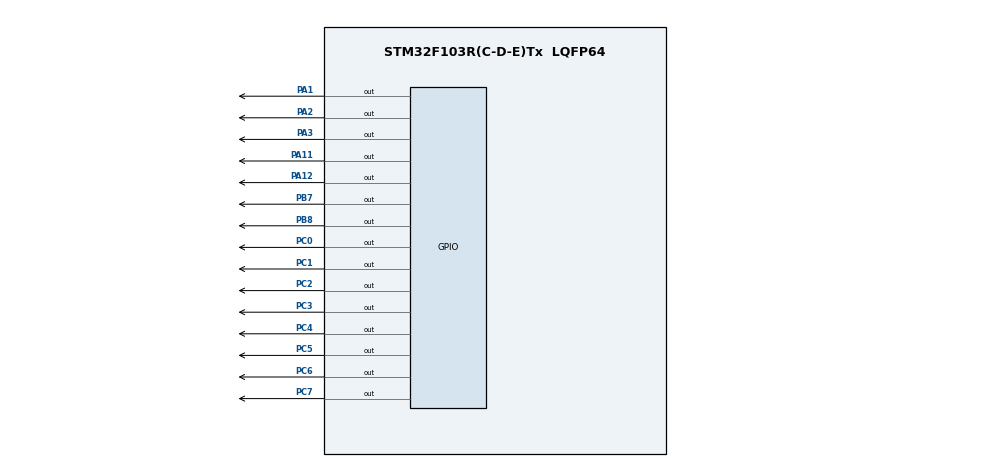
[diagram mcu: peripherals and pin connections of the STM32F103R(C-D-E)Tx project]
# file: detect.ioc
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Mcu.Family=STM32F1
Mcu.Name=STM32F103R(C-D-E)Tx
Mcu.Package=LQFP64
NVIC.PriorityGroup=NVIC_PRIORITYGROUP_4
PA1.PinState=GPIO_PIN_SET
PA1.Signal=GPIO_Output
PA11.Signal=GPIO_Output
PA12.Signal=GPIO_Output
PA2.PinState=GPIO_PIN_SET
PA2.Signal=GPIO_Output
PA3.PinState=GPIO_PIN_SET
PA3.Signal=GPIO_Output
PB7.PinState=GPIO_PIN_SET
PB7.Signal=GPIO_Output
PB8.PinState=GPIO_PIN_SET
PB8.Signal=GPIO_Output
PC0.PinState=GPIO_PIN_SET
PC0.Signal=GPIO_Output
PC1.PinState=GPIO_PIN_SET
PC1.Signal=GPIO_Output
PC2.PinState=GPIO_PIN_SET
PC2.Signal=GPIO_Output
PC3.PinState=GPIO_PIN_SET
PC3.Signal=GPIO_Output
PC4.PinState=GPIO_PIN_SET
PC4.Signal=GPIO_Output
PC5.PinState=GPIO_PIN_SET
PC5.Signal=GPIO_Output
PC6.PinState=GPIO_PIN_SET
PC6.Signal=GPIO_Output
PC7.PinState=GPIO_PIN_SET
PC7.Signal=GPIO_Output
PD0-OSC_IN.Mode=HSE-External-Oscillator
PD0-OSC_IN.Signal=RCC_OSC_IN
PD1-OSC_OUT.Mode=HSE-External-Oscillator
PD1-OSC_OUT.Signal=RCC_OSC_OUT
ProjectManager.HeapSize=0x200
ProjectManager.StackSize=0x400
ProjectManager.TargetToolchain=MDK-ARM V5
RCC.AHBFreq_Value=72000000
RCC.APB1CLKDivider=RCC_HCLK_DIV2
RCC.APB1Freq_Value=36000000
RCC.APB1TimFreq_Value=72000000
RCC.APB2CLKDivider=RCC_HCLK_DIV2
RCC.APB2Freq_Value=36000000
RCC.APB2TimFreq_Value=72000000
RCC.HCLKFreq_Value=72000000
RCC.PLLMUL=RCC_PLL_MUL9
RCC.PLLSourceVirtual=RCC_PLLSOURCE_HSE
RCC.SYSCLKFreq_VALUE=72000000
RCC.SYSCLKSource=RCC_SYSCLKSOURCE_PLLCLK
RCC.USBFreq_Value=72000000
VP_SYS_VS_ND.Mode=No_Debug
board=custom

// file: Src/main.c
/* USER CODE BEGIN Header */
/**
  ******************************************************************************
  * @file           : main.c
  * @brief          : Main program body
  ******************************************************************************
  * @attention
  *
  * <h2><center>&copy; Copyright (c) 2020 STMicroelectronics.
  * All rights reserved.</center></h2>
  *
  * This software component is licensed by ST under BSD 3-Clause license,
  * the "License"; You may not use this file except in compliance with the
  * License. You may obtain a copy of the License at:
  *                        opensource.org/licenses/BSD-3-Clause
  *
  ******************************************************************************
  */
/* USER CODE END Header */

#include "main.h"
#include "tim.h"
#include "usart.h"
#include "gpio.h"

/* USER CODE BEGIN Includes */
#include "sht.h"
#include "LCD1602.h"
/* USER CODE END Includes */

void SystemClock_Config(void);

int main(void)
{
    /* USER CODE BEGIN 1 */
		char t[] = "temp:";
		char h[] = "humi:";
		int temp = 0;
    int humi = 0;
    /* USER CODE END 1 */

    /* MCU Configuration--------------------------------------------------------*/

    /* Reset of all peripherals, Initializes the Flash interface and the Systick. */
    HAL_Init();

    /* Configure the system clock */
    SystemClock_Config();

    /* Initialize all configured peripherals */
    MX_GPIO_Init();

    /* USER CODE BEGIN 2 */
		LCD_Init();
		LCD_ShowString(0, 0, t);
		LCD_ShowString(1, 0, h);

    while(SHT2x_Init());

		char hh[] = "%RH", tt[] = "C";
		int flag1 = 0, flag2 = 0;
    /* USER CODE END 2 */

    /* Infinite loop */
    while (1)
    {

        /* USER CODE BEGIN 3 */
        temp = (int)SHT2x_GetTempPoll();
				humi = (int)SHT2x_GetHumiPoll();

				if(temp > 30 || temp < 20)
				{
					HAL_GPIO_WritePin(GPIOB, GPIO_PIN_8, GPIO_PIN_RESET); // alarm
					if(temp > 30)
					{
						HAL_GPIO_WritePin(GPIOB, GPIO_PIN_10, GPIO_PIN_RESET); // cool
						HAL_GPIO_WritePin(GPIOB, GPIO_PIN_12, GPIO_PIN_SET); //
					}
					else
					{
						HAL_GPIO_WritePin(GPIOB, GPIO_PIN_12, GPIO_PIN_RESET); // heat
						HAL_GPIO_WritePin(GPIOB, GPIO_PIN_10, GPIO_PIN_SET);
					}

				}
				else
				{
					// shut
					HAL_GPIO_WritePin(GPIOB, GPIO_PIN_8, GPIO_PIN_SET);
					HAL_GPIO_WritePin(GPIOB, GPIO_PIN_10, GPIO_PIN_SET);
					HAL_GPIO_WritePin(GPIOB, GPIO_PIN_12, GPIO_PIN_SET);
				}

				HAL_Delay(100);
				if(humi < 80 || humi > 90)
				{
					HAL_GPIO_WritePin(GPIOB, GPIO_PIN_7, GPIO_PIN_RESET); //alarm
					if(humi < 80) HAL_GPIO_WritePin(GPIOB, GPIO_PIN_11, GPIO_PIN_RESET); // water
					else HAL_GPIO_WritePin(GPIOB, GPIO_PIN_11, GPIO_PIN_SET);
				}
				else
				{
					HAL_GPIO_WritePin(GPIOB, GPIO_PIN_7, GPIO_PIN_SET);
					HAL_GPIO_WritePin(GPIOB, GPIO_PIN_11, GPIO_PIN_SET);
				}

				LCD_ShowNum(1, 6, temp, 2);
				if(!flag1)
				{
					LCD_ShowString(0, 7, tt);
					flag1 = 1;
				}
				LCD_ShowNum(2, 6, humi, 2);
				if(!flag2)
				{
					LCD_ShowString(1, 7, hh);
					flag2 = 1;
				}
        HAL_Delay(100);
    }
    /* USER CODE END 3 */
}

void SystemClock_Config(void)
{
    RCC_OscInitTypeDef RCC_OscInitStruct = {0};
    RCC_ClkInitTypeDef RCC_ClkInitStruct = {0};

    /** Initializes the CPU, AHB and APB busses clocks
    */
    RCC_OscInitStruct.OscillatorType = RCC_OSCILLATORTYPE_HSE;
    RCC_OscInitStruct.HSEState = RCC_HSE_ON;
    RCC_OscInitStruct.HSEPredivValue = RCC_HSE_PREDIV_DIV1;
    RCC_OscInitStruct.HSIState = RCC_HSI_ON;
    RCC_OscInitStruct.PLL.PLLState = RCC_PLL_ON;
    RCC_OscInitStruct.PLL.PLLSource = RCC_PLLSOURCE_HSE;
    RCC_OscInitStruct.PLL.PLLMUL = RCC_PLL_MUL9;
    if (HAL_RCC_OscConfig(&RCC_OscInitStruct) != HAL_OK)
    {
        Error_Handler();
    }
    /** Initializes the CPU, AHB and APB busses clocks
    */
    RCC_ClkInitStruct.ClockType = RCC_CLOCKTYPE_HCLK|RCC_CLOCKTYPE_SYSCLK
                                  |RCC_CLOCKTYPE_PCLK1|RCC_CLOCKTYPE_PCLK2;
    RCC_ClkInitStruct.SYSCLKSource = RCC_SYSCLKSOURCE_PLLCLK;
    RCC_ClkInitStruct.AHBCLKDivider = RCC_SYSCLK_DIV1;
    RCC_ClkInitStruct.APB1CLKDivider = RCC_HCLK_DIV2;
    RCC_ClkInitStruct.APB2CLKDivider = RCC_HCLK_DIV1;

    if (HAL_RCC_ClockConfig(&RCC_ClkInitStruct, FLASH_LATENCY_2) != HAL_OK)
    {
        Error_Handler();
    }
}

void Error_Handler(void)
{
}

/************************ (C) COPYRIGHT STMicroelectronics *****END OF FILE****/
